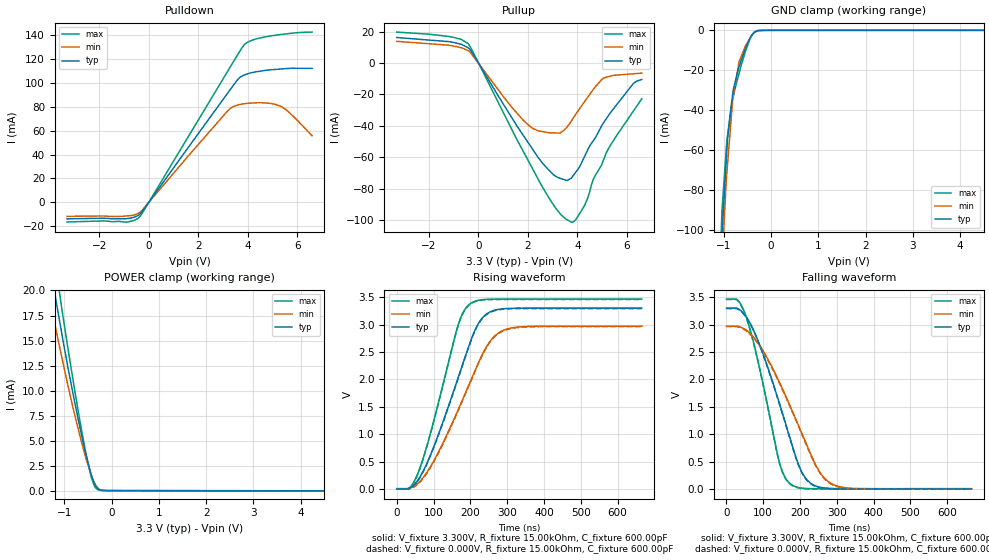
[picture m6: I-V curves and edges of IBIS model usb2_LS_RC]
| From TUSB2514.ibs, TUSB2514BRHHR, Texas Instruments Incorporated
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|   USB 2.0 High Speed mode, for DP/DM pin 750KHz with recommended
|   Rload and Cload of 15kOhm and 600pF
[Model]   usb2_LS_RC
Model_type   I/O
Polarity   Non-Inverting
Enable   Active-High
Vmeas = 1.32V
Vref = 0
Rref = 15000
Cref = 600pF
Vinl = 0.8V
Vinh = 2.0V
|   typ   min   max
|   (nom PVT)   (Fast PVT)   (slow PVT)
C_comp   9.3159pF   9.1524pF   9.4841pF
[Voltage Range]   3.3   2.97   3.465
[Temperature Range]   27   105   -40
[Pullup Reference]   3.3   2.97   3.465
[Pulldown Reference]   -0   -0   -0
[Power Clamp Reference]   3.3   2.97   3.465
[GND Clamp Reference]   -0   -0   -0
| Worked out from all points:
|   slope of the pulldown table from 0 to 0.495 V, typ, clamps not added: 34.7 ohm
|   slope of the pullup table from 0 to 0.495 V, typ, clamps not added: 38.2 ohm
|   GND clamp passes 1 mA (typ) near -0.35 V on its own axis
|   POWER clamp passes 1 mA (typ) near -0.38 V on its own axis
|   falling waveform, V_fixture 3.300V, R_fixture 15.00kOhm, C_fixture 600.00pF: 20-80 % time 95ns typ, 120ns min, 66.7ns max; typ from 3.3 V to 0.008 V
|   rising waveform, V_fixture 3.300V, R_fixture 15.00kOhm, C_fixture 600.00pF: 20-80 % time 103ns typ, 120ns min, 79.8ns max; typ from 0.008 V to 3.3 V
|   rising waveform, V_fixture 0.000V, R_fixture 15.00kOhm, C_fixture 600.00pF: 20-80 % time 103ns typ, 119ns min, 79.8ns max; typ from 0 V to 3.29 V
|   falling waveform, V_fixture 0.000V, R_fixture 15.00kOhm, C_fixture 600.00pF: 20-80 % time 95.1ns typ, 120ns min, 66.7ns max; typ from 3.29 V to 0 V
[Pulldown]
|   Voltage   I(typ)   I(min)   I(max)
-3.3V     -13.8mA    -11.67mA   -16.38mA
-1.818V   -13.22mA   -11.38mA   -15.5mA
-933.8mV  -13.69mA   -11.39mA   -16.56mA
-393.4mV  -10.5mA    -8.814mA   -12.71mA
3.144V    90.09mA    75.48mA    108.1mA
3.518V    100.7mA    80.99mA    120.9mA
3.716V    105mA      82.04mA    127.7mA
3.979V    107.4mA    82.87mA    133.8mA
4.553V    109.9mA    83.38mA    137.7mA
5.239V    111.4mA    81.15mA    140.2mA
5.684V    112.1mA    75.09mA    141.3mA
6.6V      112.1mA    55.7mA     142.4mA
[GND Clamp]
|   Voltage   I(typ)   I(min)   I(max)
-3.3V     -2.986A    -2.594A    -3.408A
-1.078V   -130.7mA   -136.1mA   -123.1mA
-1.035V   -101.8mA   -116.7mA   -90.38mA
-933.8mV  -60.8mA    -71.89mA   -55.6mA
-917.7mV  -54.32mA   -67.11mA   -52.63mA
-830mV    -36.19mA   -40.99mA   -36.44mA
-800mV    -30mA      -33.29mA   -33.41mA
-672.6mV  -18.05mA   -15.62mA   -21.44mA
-537.4mV  -9.128mA   -7.685mA   -10.37mA
-452.6mV  -4.449mA   -4.267mA   -4.821mA
-311.3mV  -500.4uA   -565.3uA   -312.4uA
6.6V      0A         0A         0A
[Pullup]
|   Voltage   I(typ)   I(min)   I(max)
-3.3V     16.19mA    13.77mA    19.64mA
-422.2mV  9.743mA    7.891mA    12.39mA
1.406V    -36.22mA   -29.18mA   -44.02mA
2.198V    -55mA      -41.55mA   -67.51mA
3.296V    -73.26mA   -44.5mA    -95.68mA
3.744V    -73.22mA   -37.02mA   -101mA
4.291V    -59.28mA   -24.5mA    -90.47mA
4.637V    -49.45mA   -16.86mA   -74.15mA
4.997V    -39.36mA   -10.25mA   -63.91mA
5.347V    -31.31mA   -8.288mA   -51.9mA
6.247V    -13.27mA   -6.876mA   -30.86mA
6.6V      -10.45mA   -6.447mA   -22.73mA
[POWER Clamp]
|   Voltage   I(typ)   I(min)   I(max)
-3.3V     96.14mA    80.42mA    114.3mA
-1.357V   24.07mA    20.31mA    28.32mA
-1.197V   19.63mA    16.62mA    22.94mA
-1.078V   16.4mA     13.92mA    19.06mA
-917.7mV  12.22mA    10.44mA    14.11mA
-762.7mV  8.497mA    7.289mA    9.602mA
-540.3mV  3.645mA    3.234mA    3.714mA
-422.2mV  1.516mA    1.529mA    1.289mA
-358.7mV  704.2uA    786.5uA    480.4uA
-291.5mV  239.5uA    302.9uA    123.9uA
-75.48mV  29.65uA    23.12uA    37.69uA
6.6V      0A         0A         0A
[Ramp]
R_load = 15.00kOhm
|   typ   min   max
dV/dt_r   1.974V/103.338ns   1.776V/119.335ns   2.074V/79.676ns
dV/dt_f   1.975V/94.981ns   1.777V/119.587ns   2.074V/66.677ns
[Falling Waveform]
V_fixture = 3.300V
V_fixture_min = 2.970V
V_fixture_max = 3.465V
R_fixture = 15.00kOhm
C_fixture = 600.00pF
|   Time   V(typ)   V(min)   V(max)
0s        3.299V     2.969V     3.464V
29.63ns   3.293V     2.969V     3.451V
53.58ns   3.143V     2.898V     3.14V
85.5ns    2.713V     2.667V     2.343V
143.7ns   1.569V     1.951V     494.9mV
175ns     879.6mV    1.484V     89.73mV
218.8ns   168.9mV    797mV      11.37mV
255.7ns   33.06mV    291.2mV    6.896mV
290.3ns   11.2mV     82.6mV     6.651mV
666ns     7.603mV    8.069mV    6.676mV
[Rising Waveform]
V_fixture = 3.300V
V_fixture_min = 2.970V
V_fixture_max = 3.465V
R_fixture = 15.00kOhm
C_fixture = 600.00pF
|   Time   V(typ)   V(min)   V(max)
0s        7.603mV    8.069mV    6.676mV
34.47ns   18.06mV    13.95mV    27.35mV
58.15ns   170.3mV    108.1mV    298.3mV
102.1ns   798.4mV    531.7mV    1.284V
166.6ns   2.024V     1.441V     2.984V
198.1ns   2.648V     1.93V      3.371V
236.8ns   3.15V      2.511V     3.456V
267.1ns   3.263V     2.796V     3.463V
297.7ns   3.292V     2.914V     3.464V
666ns     3.299V     2.969V     3.464V
[Rising Waveform]
V_fixture = 0.000V
V_fixture_min = 0.000V
V_fixture_max = 0.000V
R_fixture = 15.00kOhm
C_fixture = 600.00pF
|   Time   V(typ)   V(min)   V(max)
0s        2.675uV    8.032uV    3.659uV
34.7ns    9.552mV    5.136mV    20.11mV
58.18ns   158.2mV    95.07mV    288.4mV
102.1ns   785mV      516.7mV    1.273V
166.7ns   2.015V     1.429V     2.977V
198.2ns   2.637V     1.917V     3.364V
236.8ns   3.14V      2.497V     3.448V
267.4ns   3.255V     2.786V     3.456V
297.9ns   3.283V     2.905V     3.457V
666ns     3.291V     2.96V      3.457V
[Falling Waveform]
V_fixture = 0.000V
V_fixture_min = 0.000V
V_fixture_max = 0.000V
R_fixture = 15.00kOhm
C_fixture = 600.00pF
|   Time   V(typ)   V(min)   V(max)
0s        3.291V     2.96V      3.457V
29.38ns   3.285V     2.96V      3.445V
53.48ns   3.13V      2.884V     3.131V
85.45ns   2.699V     2.65V      2.332V
143.5ns   1.558V     1.936V     488.1mV
174.8ns   869.1mV    1.47V      82.96mV
218.6ns   160.3mV    784.2mV    4.648mV
255.2ns   25.45mV    282.1mV    218.6uV
290ns     3.518mV    73.48mV    -23.23uV
666ns     2.675uV    8.032uV    3.659uV
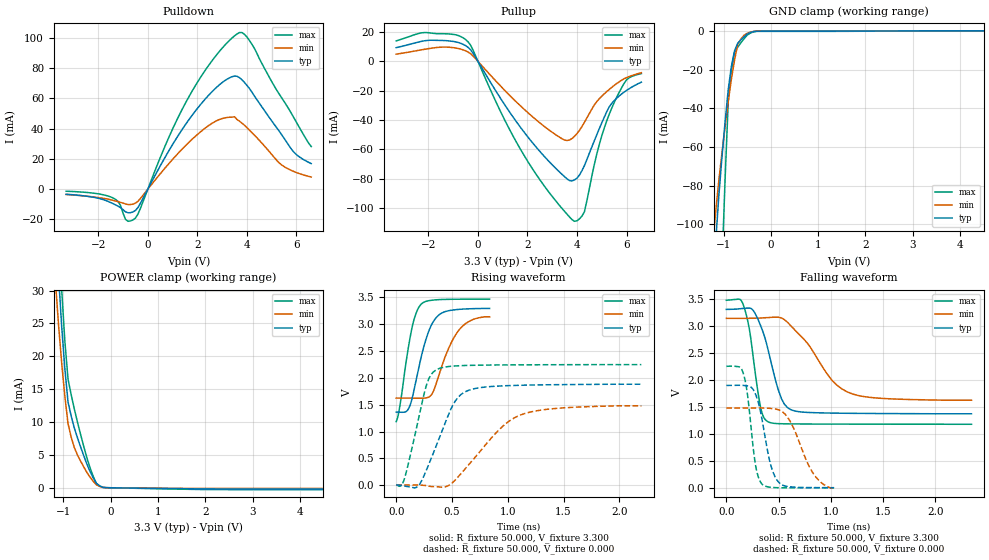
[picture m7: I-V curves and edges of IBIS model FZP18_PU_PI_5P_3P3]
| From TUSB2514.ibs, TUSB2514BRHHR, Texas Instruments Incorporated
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|   Model Cell FZP18_PU_PI_5P_3P3
|BC3340DSHYPBFZP18_PU_PI_5P_3P3
[Model]   FZP18_PU_PI_5P_3P3
Model_type   I/O
Polarity   Non-Inverting
Enable   Active-Low
Vinl =  0.8V
Vinh =  2V
Cref =  7pF
Rref =  100.00M
Vref =  0V
Vmeas =  1.65
C_comp   1.726631p   1.655247p   2.290856p
[Model Spec]
Vinl   0.8V   0.8V   0.8V
Vinh   2V   2V   2V
[Temperature Range]   25   125   -40
[Voltage Range]   3.3   3.135   3.465
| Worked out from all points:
|   slope of the pulldown table from 0 to 0.495 V, typ, clamps not added: 32.6 ohm
|   slope of the pullup table from 0 to 0.495 V, typ, clamps not added: 35.4 ohm
|   GND clamp passes 1 mA (typ) near -0.44 V on its own axis
|   POWER clamp passes 1 mA (typ) near -0.33 V on its own axis
|   rising waveform, R_fixture 50.000, V_fixture 3.300: 20-80 % time 142ps typ, 179ps min, 105ps max; typ from 1.36 V to 3.29 V
|   rising waveform, R_fixture 50.000, V_fixture 0.000: 20-80 % time 222ps typ, 390ps min, 147ps max; typ from 0.004 V to 1.88 V
|   falling waveform, R_fixture 50.000, V_fixture 3.300: 20-80 % time 163ps typ, 345ps min, 101ps max; typ from 3.3 V to 1.37 V
|   falling waveform, R_fixture 50.000, V_fixture 0.000: 20-80 % time 117ps typ, 198ps min, 80.1ps max; typ from 1.9 V to 0.008 V
[POWER_clamp]
|   voltage   I(typ)   I(min)   I(max)
-3.3V     369.6mA    284.7mA    471.9mA
-1.167V   41.09mA    31.45mA    51.3mA
-1.1V     32.22mA    24.75mA    39.99mA
-1.033V   24.47mA    18.91mA    30.11mA
-966.7mV  18.08mA    13.91mA    22.28mA
-900mV    13.06mA    9.755mA    16.53mA
-766.7mV  9.1mA      6.117mA    11.98mA
-500mV    3.584mA    2.323mA    4.526mA
-300mV    669.8uA    454.1uA    663.4uA
-233.3mV  297.2uA    212.5uA    281.7uA
1.9V      -169.8uA   -96.12uA   -257.8uA
6.6V      -184.2uA   -100.3uA   -287uA
[Pulldown]
|   voltage   I(typ)   I(min)   I(max)
-3.3V     -3.365mA   -3.488mA   -1.337mA
-1.5V     -8.823mA   -6.978mA   -5.127mA
-1.2V     -11.25mA   -8.255mA   -8.14mA
-900mV    -14.96mA   -9.762mA   -19.97mA
-500mV    -14.05mA   -9.217mA   -19.12mA
1.7V      46.86mA    31.63mA    62.28mA
2.9V      69.15mA    46.14mA    91.29mA
3.7V      73.78mA    44.98mA    103.6mA
4.2V      64.34mA    37.49mA    95.95mA
5.4V      36.15mA    16.09mA    60.58mA
5.9V      24.48mA    11.69mA    47.2mA
6.6V      16.92mA    8.046mA    28.22mA
[Pullup]
|   voltage   I(typ)   I(min)   I(max)
-3.3V     9.309mA    4.903mA    13.95mA
-2.1V     14.15mA    8.36mA     19.61mA
-900mV    13.29mA    9.083mA    18.12mA
-400mV    9.542mA    6.366mA    13.33mA
1.8V      -46.88mA   -31.69mA   -62.38mA
3.4V      -77.19mA   -52.88mA   -100.5mA
3.9V      -80.91mA   -51.11mA   -109.2mA
4.3V      -71.16mA   -41.65mA   -102.6mA
4.9V      -46.04mA   -25.54mA   -56.79mA
5.5V      -26.88mA   -16.5mA    -28.23mA
6V        -19.88mA   -11.14mA   -12.69mA
6.6V      -14.22mA   -7.771mA   -8.395mA
[GND_clamp]
|   voltage   I(typ)   I(min)   I(max)
-3.3V     -996.3mA   -831.9mA   -2.048A
-1.233V   -134.2mA   -111.4mA   -283.3mA
-1.167V   -109.2mA   -93.71mA   -227.5mA
-1.1V     -85.34mA   -77.42mA   -172.4mA
-1.033V   -65.28mA   -63.16mA   -121.7mA
-966.7mV  -46.91mA   -49.48mA   -76.37mA
-900mV    -30.23mA   -36.37mA   -36.29mA
-833.3mV  -18.18mA   -24.84mA   -20.51mA
-766.7mV  -10.24mA   -15.04mA   -11.22mA
-700mV    -6.403mA   -6.978mA   -8.448mA
-500mV    -1.721mA   -1.293mA   -2.228mA
6.6V      0A         0A         0A
[Ramp]
| variable   typ   min   max
dV/dt_f   1.178022/0.1660698n  0.9143006/0.3655049n   1.388552/0.1021699n
dV/dt_r   1.166352/0.2292052n  0.9058277/0.4208237n   1.381682/0.1492375n
R_load = 50
[Rising Waveform]
R_fixture = 50.000
V_fixture = 3.300
V_fixture_min = 3.135
V_fixture_max = 3.465
|  time   V(typ)   V(min)   V(max)
0s        1.362V     1.623V     1.185V
30ps      1.361V     1.623V     1.443V
112.5ps   1.434V     1.623V     2.607V
157.5ps   1.751V     1.622V     3.068V
210ps     2.259V     1.621V     3.337V
318ps     2.993V     1.692V     3.444V
381ps     3.168V     2.038V     3.455V
481.5ps   3.254V     2.602V     3.462V
580.5ps   3.277V     2.933V     3.464V
837ps     3.291V     3.135V     3.465V
[Rising Waveform]
R_fixture = 50.000
V_fixture = 0.000
V_fixture_min = 0.000
V_fixture_max = 0.000
|  time   V(typ)   V(min)   V(max)
0s        3.596mV    4.765mV    8.944mV
75ps      -11.83mV   4.772mV    132.1mV
202.5ps   -715.8uV   4.082mV    1.262V
280.5ps   332.3mV    -10.85mV   1.922V
367.5ps   780.7mV    -27.22mV   2.158V
529.5ps   1.57V      99.92mV    2.221V
655.5ps   1.773V     396.1mV    2.232V
934.5ps   1.849V     1.059V     2.24V
1.11ns    1.861V     1.306V     2.242V
2.197ns   1.881V     1.479V     2.246V
[Falling Waveform]
R_fixture = 50.000
V_fixture = 3.300
V_fixture_min = 3.135
V_fixture_max = 3.465
|  time   V(typ)   V(min)   V(max)
0s        3.3V       3.135V     3.469V
166.5ps   3.318V     3.135V     3.364V
219ps     3.325V     3.136V     2.954V
328.5ps   3V         3.141V     1.489V
405ps     2.513V     3.15V      1.22V
528ps     1.652V     3.142V     1.189V
637.5ps   1.435V     2.958V     1.185V
1.022ns   1.386V     1.971V     1.182V
1.157ns   1.382V     1.778V     1.182V
2.348ns   1.373V     1.623V     1.179V
[Falling Waveform]
R_fixture = 50.000
V_fixture = 0.000
V_fixture_min = 0.000
V_fixture_max = 0.000
|  time   V(typ)   V(min)   V(max)
0s        1.896V     1.479V     2.249V
159ps     1.897V     1.479V     2.14V
204ps     1.887V     1.48V      1.708V
280.5ps   1.73V      1.48V      414.6mV
340.5ps   1.283V     1.48V      76.32mV
424.5ps   430.7mV    1.472V     15.09mV
504ps     102.7mV    1.444V     7.147mV
624ps     21.73mV    1.189V     5.664mV
841.5ps   9.635mV    245.8mV    5.417mV
1.032ns   8.135mV    4.765mV    5.326mV
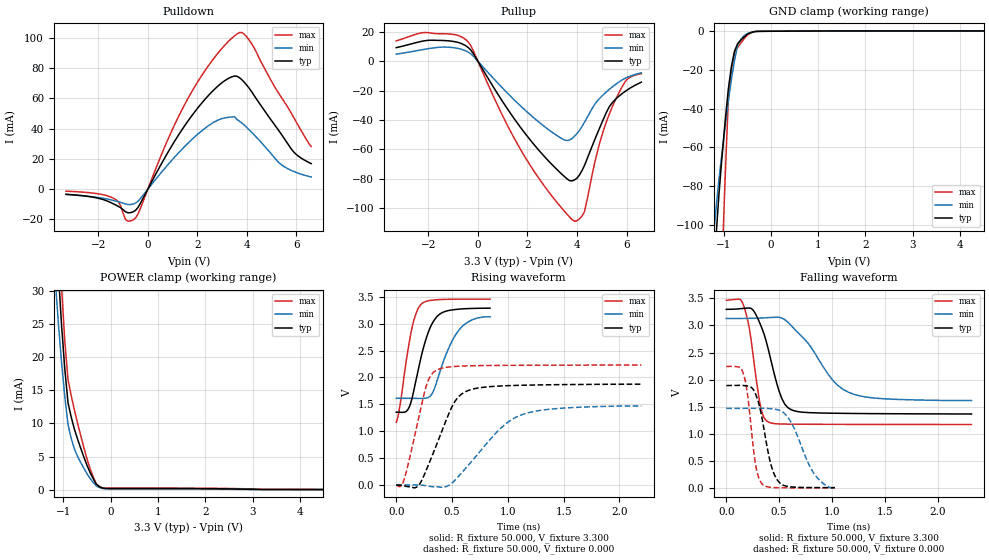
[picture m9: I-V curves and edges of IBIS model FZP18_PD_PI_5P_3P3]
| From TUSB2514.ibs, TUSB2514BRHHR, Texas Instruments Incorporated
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|   Model Cell FZP18_PD_PI_5P_3P3
|BC3340DSHYPBFZP18_PD_PI_5P_3P3
[Model]   FZP18_PD_PI_5P_3P3
Model_type   I/O
Polarity   Non-Inverting
Enable   Active-Low
Vinl =  0.8V
Vinh =  2V
Cref =  7pF
Rref =  100.00M
Vref =  0V
Vmeas =  1.65
C_comp   1.726631p   1.655247p   2.290856p
[Model Spec]
Vinl   0.8V   0.8V   0.8V
Vinh   2V   2V   2V
[Temperature Range]   25   125   -40
[Voltage Range]   3.3   3.135   3.465
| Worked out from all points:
|   slope of the pulldown table from 0 to 0.495 V, typ, clamps not added: 32.6 ohm
|   slope of the pullup table from 0 to 0.495 V, typ, clamps not added: 35.4 ohm
|   GND clamp passes 1 mA (typ) near -0.45 V on its own axis
|   POWER clamp passes 1 mA (typ) near -0.32 V on its own axis
|   rising waveform, R_fixture 50.000, V_fixture 3.300: 20-80 % time 143ps typ, 180ps min, 106ps max; typ from 1.35 V to 3.29 V
|   rising waveform, R_fixture 50.000, V_fixture 0.000: 20-80 % time 222ps typ, 391ps min, 148ps max; typ from 0 V to 1.88 V
|   falling waveform, R_fixture 50.000, V_fixture 3.300: 20-80 % time 163ps typ, 344ps min, 101ps max; typ from 3.3 V to 1.36 V
|   falling waveform, R_fixture 50.000, V_fixture 0.000: 20-80 % time 117ps typ, 197ps min, 80ps max; typ from 1.89 V to 0.004 V
[POWER_clamp]
|   voltage   I(typ)   I(min)   I(max)
-3.3V     369.7mA    284.7mA    471.9mA
-1.167V   41.13mA    31.48mA    51.35mA
-1.1V     32.27mA    24.79mA    40.05mA
-1.033V   24.52mA    18.96mA    30.17mA
-966.7mV  18.14mA    13.96mA    22.35mA
-900mV    13.12mA    9.808mA    16.6mA
-766.7mV  9.178mA    6.178mA    12.08mA
-500mV    3.691mA    2.401mA    4.668mA
-300mV    797.8uA    544.5uA    836.8uA
-233.3mV  432.2uA    307uA      465.8uA
-100mV    167.9uA    118.1uA    229.7uA
6.6V      0A         0A         0A
[Pulldown]
|   voltage   I(typ)   I(min)   I(max)
-3.3V     -3.365mA   -3.488mA   -1.337mA
-1.5V     -8.823mA   -6.978mA   -5.127mA
-1.2V     -11.25mA   -8.255mA   -8.14mA
-900mV    -14.96mA   -9.762mA   -19.97mA
-500mV    -14.05mA   -9.217mA   -19.12mA
1.7V      46.86mA    31.63mA    62.28mA
2.9V      69.16mA    46.14mA    91.29mA
3.7V      73.78mA    44.98mA    103.6mA
4.2V      64.34mA    37.49mA    95.96mA
5.4V      36.15mA    16.09mA    60.58mA
5.9V      24.48mA    11.69mA    47.2mA
6.6V      16.92mA    8.046mA    28.22mA
[Pullup]
|   voltage   I(typ)   I(min)   I(max)
-3.3V     9.309mA    4.903mA    13.95mA
-2.1V     14.15mA    8.36mA     19.61mA
-900mV    13.29mA    9.083mA    18.12mA
-400mV    9.542mA    6.366mA    13.33mA
1.8V      -46.88mA   -31.69mA   -62.38mA
3.4V      -77.19mA   -52.87mA   -100.5mA
3.9V      -80.91mA   -51.11mA   -109.2mA
4.3V      -71.16mA   -41.65mA   -102.6mA
4.9V      -46.04mA   -25.54mA   -56.79mA
5.5V      -26.88mA   -16.5mA    -28.23mA
6V        -19.88mA   -11.14mA   -12.69mA
6.6V      -14.22mA   -7.771mA   -8.395mA
[GND_clamp]
|   voltage   I(typ)   I(min)   I(max)
-3.3V     -996.3mA   -831.9mA   -2.048A
-1.233V   -134.2mA   -111.4mA   -283.3mA
-1.167V   -109.2mA   -93.71mA   -227.4mA
-1.1V     -85.33mA   -77.41mA   -172.4mA
-1.033V   -65.26mA   -63.15mA   -121.7mA
-966.7mV  -46.88mA   -49.47mA   -76.32mA
-900mV    -30.19mA   -36.36mA   -36.22mA
-833.3mV  -18.13mA   -24.82mA   -20.41mA
-766.7mV  -10.18mA   -15.02mA   -11.12mA
-700mV    -6.333mA   -6.946mA   -8.325mA
-500mV    -1.622mA   -1.243mA   -2.064mA
6.6V      163.3uA    124.6uA    227.9uA
[Ramp]
| variable   typ   min   max
dV/dt_f   1.180283/0.1658519n  0.9157424/0.3647765n   1.391553/0.1020536n
dV/dt_r   1.164918/0.2296956n  0.9045015/0.4214654n   1.380389/0.1496363n
R_load = 50
[Rising Waveform]
R_fixture = 50.000
V_fixture = 3.300
V_fixture_min = 3.135
V_fixture_max = 3.465
|  time   V(typ)   V(min)   V(max)
0s        1.355V     1.613V     1.168V
36ps      1.353V     1.613V     1.511V
112.5ps   1.432V     1.613V     2.6V
157.5ps   1.756V     1.612V     3.058V
210ps     2.261V     1.611V     3.328V
304.5ps   2.93V      1.653V     3.432V
381ps     3.163V     2.036V     3.448V
469.5ps   3.245V     2.542V     3.454V
568.5ps   3.272V     2.897V     3.456V
840ps     3.288V     3.129V     3.457V
[Rising Waveform]
R_fixture = 50.000
V_fixture = 0.000
V_fixture_min = 0.000
V_fixture_max = 0.000
|  time   V(typ)   V(min)   V(max)
0s        224.4uV    -20.69uV   -747.6uV
64.5ps    -10.71mV   -9.329uV   65.17mV
202.5ps   -1.761mV   -771.7uV   1.259V
280.5ps   334mV      -16.22mV   1.912V
367.5ps   781.8mV    -32.24mV   2.143V
528ps     1.562V     93.72mV    2.206V
679.5ps   1.781V     450.2mV    2.218V
958.5ps   1.845V     1.098V     2.225V
1.158ns   1.857V     1.331V     2.227V
2.196ns   1.875V     1.469V     2.231V
[Falling Waveform]
R_fixture = 50.000
V_fixture = 3.300
V_fixture_min = 3.135
V_fixture_max = 3.465
|  time   V(typ)   V(min)   V(max)
0s        3.297V     3.129V     3.465V
166.5ps   3.315V     3.13V      3.352V
217.5ps   3.322V     3.131V     2.949V
327ps     2.996V     3.136V     1.48V
403.5ps   2.508V     3.145V     1.211V
526.5ps   1.645V     3.136V     1.179V
636ps     1.427V     2.952V     1.176V
1.02ns    1.378V     1.961V     1.173V
1.154ns   1.375V     1.768V     1.172V
2.321ns   1.365V     1.613V     1.17V
[Falling Waveform]
R_fixture = 50.000
V_fixture = 0.000
V_fixture_min = 0.000
V_fixture_max = 0.000
|  time   V(typ)   V(min)   V(max)
0s        1.889V     1.469V     2.242V
157.5ps   1.891V     1.469V     2.132V
204ps     1.88V      1.47V      1.676V
279ps     1.723V     1.47V      405.8mV
339ps     1.275V     1.47V      69.78mV
423ps     423.2mV    1.462V     9.454mV
502.5ps   97.06mV    1.434V     1.732mV
622.5ps   17.1mV     1.178V     254.5uV
840ps     5.328mV    237.1mV    98.49uV
1.028ns   3.903mV    -20.69uV   80.3uV
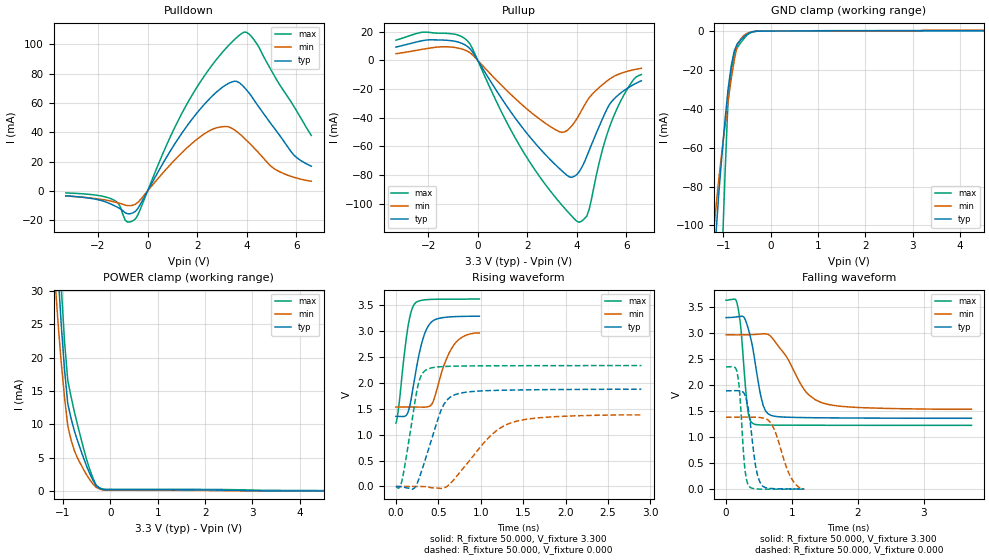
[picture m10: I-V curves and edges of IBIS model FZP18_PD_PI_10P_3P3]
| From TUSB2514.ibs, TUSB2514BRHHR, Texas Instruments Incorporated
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|   Model Cell FZP18_PD_PI_10P_3P3
|BC3340DSHYPBFZP18_PD_PI_10P_3P3
[Model]   FZP18_PD_PI_10P_3P3
Model_type   I/O
Polarity   Non-Inverting
Enable   Active-Low
Vinl =  0.8V
Vinh =  2V
Cref =  7pF
Rref =  100.00M
Vref =  0V
Vmeas =  1.65
C_comp   1.726631p   1.582948p   1.812054p
[Model Spec]
Vinl   0.8V   0.8V   0.8V
Vinh   2V   2V   2V
[Temperature Range]   25   125   -40
[Voltage Range]   3.3   2.97   3.63
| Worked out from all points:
|   slope of the pulldown table from 0 to 0.495 V, typ, clamps not added: 32.6 ohm
|   slope of the pullup table from 0 to 0.495 V, typ, clamps not added: 35.4 ohm
|   GND clamp passes 1 mA (typ) near -0.45 V on its own axis
|   POWER clamp passes 1 mA (typ) near -0.32 V on its own axis
|   rising waveform, R_fixture 50.000, V_fixture 3.300: 20-80 % time 143ps typ, 187ps min, 103ps max; typ from 1.35 V to 3.29 V
|   rising waveform, R_fixture 50.000, V_fixture 0.000: 20-80 % time 223ps typ, 453ps min, 139ps max; typ from 0 V to 1.88 V
|   falling waveform, R_fixture 50.000, V_fixture 3.300: 20-80 % time 163ps typ, 411ps min, 93.4ps max; typ from 3.3 V to 1.36 V
|   falling waveform, R_fixture 50.000, V_fixture 0.000: 20-80 % time 117ps typ, 220ps min, 74.1ps max; typ from 1.89 V to 0.003 V
[POWER_clamp]
|   voltage   I(typ)   I(min)   I(max)
-3.3V     369.7mA    284.8mA    471.9mA
-1.167V   41.13mA    31.49mA    51.34mA
-1.1V     32.27mA    24.8mA     40.05mA
-1.033V   24.52mA    18.96mA    30.17mA
-966.7mV  18.14mA    13.96mA    22.36mA
-900mV    13.12mA    9.805mA    16.61mA
-766.7mV  9.178mA    6.172mA    12.09mA
-500mV    3.69mA     2.39mA     4.685mA
-300mV    797.6uA    532.6uA    856.4uA
-233.3mV  432uA      294.9uA    485.4uA
-100mV    167.7uA    106uA      249.3uA
6.6V      0A         0A         0A
[Pulldown]
|   voltage   I(typ)   I(min)   I(max)
-3.3V     -3.365mA   -3.408mA   -1.35mA
-1.5V     -8.823mA   -6.868mA   -5.16mA
-1.2V     -11.25mA   -8.144mA   -8.194mA
-900mV    -14.96mA   -9.653mA   -20.06mA
-500mV    -14.05mA   -9.144mA   -19.19mA
1.1V      32.18mA    21.23mA    43.46mA
2.4V      61.1mA     40.13mA    81.13mA
3.4V      74.34mA    42.73mA    101.5mA
3.9V      70.64mA    35.96mA    108.3mA
5.1V      43.02mA    15.26mA    78.93mA
5.9V      24.48mA    9.306mA    57.71mA
6.6V      16.92mA    6.609mA    37.85mA
[Pullup]
|   voltage   I(typ)   I(min)   I(max)
-3.3V     9.309mA    4.668mA    14.12mA
-2.1V     14.15mA    8.14mA     19.77mA
-400mV    9.542mA    6.3mA      13.38mA
1.5V      -39.97mA   -26.45mA   -53.78mA
3.1V      -72.31mA   -48.02mA   -94.94mA
3.6V      -80.23mA   -49.04mA   -105.1mA
4.1V      -77.58mA   -37.73mA   -113mA
4.5V      -62.66mA   -25.98mA   -103.7mA
5V        -42.07mA   -17.41mA   -64.41mA
5.5V      -26.88mA   -11.08mA   -38.35mA
6.2V      -17.74mA   -6.877mA   -15.47mA
6.6V      -14.22mA   -5.549mA   -9.882mA
[GND_clamp]
|   voltage   I(typ)   I(min)   I(max)
-3.3V     -996.3mA   -831.9mA   -2.048A
-1.233V   -134.2mA   -111.3mA   -283.3mA
-1.167V   -109.2mA   -93.7mA    -227.4mA
-1.1V     -85.33mA   -77.41mA   -172.4mA
-1.033V   -65.26mA   -63.15mA   -121.7mA
-966.7mV  -46.88mA   -49.46mA   -76.33mA
-900mV    -30.19mA   -36.36mA   -36.22mA
-833.3mV  -18.13mA   -24.82mA   -20.42mA
-766.7mV  -10.18mA   -15.02mA   -11.12mA
-700mV    -6.333mA   -6.945mA   -8.328mA
-500mV    -1.622mA   -1.243mA   -2.066mA
6.6V      163.1uA    401.7uA    247.3uA
[Ramp]
| variable   typ   min   max
dV/dt_f   1.180282/0.1658335n  0.8591166/0.4354199n   1.456844/94.44807p
dV/dt_r   1.164899/0.2297027n   0.849007/0.4872346n   1.446725/0.140298n
R_load = 50
[Rising Waveform]
R_fixture = 50.000
V_fixture = 3.300
V_fixture_min = 2.970
V_fixture_max = 3.630
|  time   V(typ)   V(min)   V(max)
0s        1.355V     1.535V     1.224V
34.5ps    1.355V     1.535V     1.562V
135ps     1.408V     1.535V     3.013V
213ps     2.014V     1.535V     3.512V
312ps     2.816V     1.533V     3.6V
406.5ps   3.157V     1.562V     3.615V
577.5ps   3.268V     2.39V      3.62V
676.5ps   3.281V     2.719V     3.621V
810ps     3.288V     2.911V     3.621V
984ps     3.29V      2.965V     3.622V
[Rising Waveform]
R_fixture = 50.000
V_fixture = 0.000
V_fixture_min = 0.000
V_fixture_max = 0.000
|  time   V(typ)   V(min)   V(max)
0s        220.6uV    6.917uV    -1.188mV
70.5ps    -3.234mV   -4.707uV   107.8mV
223.5ps   -18.98mV   44.77uV    1.624V
288ps     227.8mV    -110.1uV   2.107V
373.5ps   662.5mV    -9.044mV   2.268V
567ps     1.592V     -28.21mV   2.319V
736.5ps   1.795V     238.5mV    2.327V
1.113ns   1.854V     975.1mV    2.332V
1.355ns   1.863V     1.229V     2.334V
2.894ns   1.879V     1.383V     2.337V
[Falling Waveform]
R_fixture = 50.000
V_fixture = 3.300
V_fixture_min = 2.970
V_fixture_max = 3.630
|  time   V(typ)   V(min)   V(max)
0s        3.296V     2.965V     3.629V
180ps     3.313V     2.964V     3.499V
229.5ps   3.321V     2.965V     3.035V
331.5ps   3.107V     2.967V     1.511V
418.5ps   2.617V     2.97V      1.255V
565.5ps   1.602V     2.984V     1.233V
711ps     1.407V     2.891V     1.231V
1.182ns   1.375V     1.922V     1.228V
1.46ns    1.371V     1.658V     1.228V
3.728ns   1.362V     1.535V     1.226V
[Falling Waveform]
R_fixture = 50.000
V_fixture = 0.000
V_fixture_min = 0.000
V_fixture_max = 0.000
|  time   V(typ)   V(min)   V(max)
0s        1.888V     1.383V     2.348V
171ps     1.892V     1.383V     2.226V
205.5ps   1.887V     1.383V     1.878V
283.5ps   1.817V     1.384V     417mV
345ps     1.489V     1.384V     62.47mV
451.5ps   425.6mV    1.383V     4.954mV
529.5ps   100.8mV    1.374V     913.2uV
684ps     12.58mV    1.263V     108.8uV
967.5ps   4.291mV    268.9mV    80.88uV
1.188ns   3.174mV    6.917uV    62.97uV
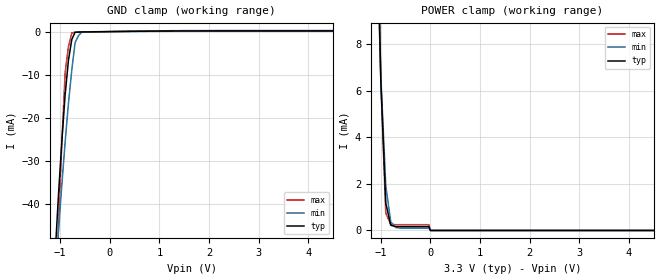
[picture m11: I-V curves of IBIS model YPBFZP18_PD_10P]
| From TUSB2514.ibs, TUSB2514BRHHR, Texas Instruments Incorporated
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|   Model Cell YPBFZP18_PD_10P
|BC3340DSHYPBFZP18_PD_10P_Input
[Model]   YPBFZP18_PD_10P
Model_type   Input
Polarity   Non-Inverting
Vinl =  0.8V
Vinh =  2V
C_comp   0.3896289p   0.315767p   0.4571448p
[Model Spec]
Vinl   0.8V   0.8V   0.8V
Vinh   2V   2V   2V
[Temperature Range]   25   125   -40
[Voltage Range]   3.3   2.97   3.63
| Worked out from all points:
|   GND clamp passes 1 mA (typ) near -0.73 V on its own axis
|   POWER clamp passes 1 mA (typ) near -0.88 V on its own axis
[POWER_clamp]
|   voltage   I(typ)   I(min)   I(max)
-3.3V     301.3mA    233.2mA    387.9mA
-1.033V   9.55mA     8.995mA    10.32mA
-1V       6.447mA    6.612mA    6.392mA
-900mV    1.174mA    1.929mA    741.9uA
-800mV    226.2uA    367.5uA    260.3uA
-700mV    166.7uA    129uA      248.8uA
-33.33mV  163.3uA    99.03uA    247.8uA
0V        0A         0A         0A
6.6V      0A         0A         0A
[GND_clamp]
|   voltage   I(typ)   I(min)   I(max)
-3.3V     -758.5mA   -699.4mA   -1.009A
-1.1V     -51.19mA   -56.68mA   -67.09mA
-1.033V   -37.57mA   -45.83mA   -44.86mA
-966.7mV  -25.35mA   -35.44mA   -25.65mA
-900mV    -14.52mA   -25.49mA   -9.465mA
-833.3mV  -6.609mA   -16.55mA   -3.407mA
-766.7mV  -1.815mA   -8.901mA   -303.1uA
-700mV    -143.7uA   -2.549mA   -154.9uA
-633.3mV  -107.9uA   -955.1uA   -139.9uA
-566.7mV  -85uA      -120.9uA   -125.4uA
1.5V      148.6uA    89.59uA    223.5uA
6.6V      163.2uA    99.09uA    247.3uA
